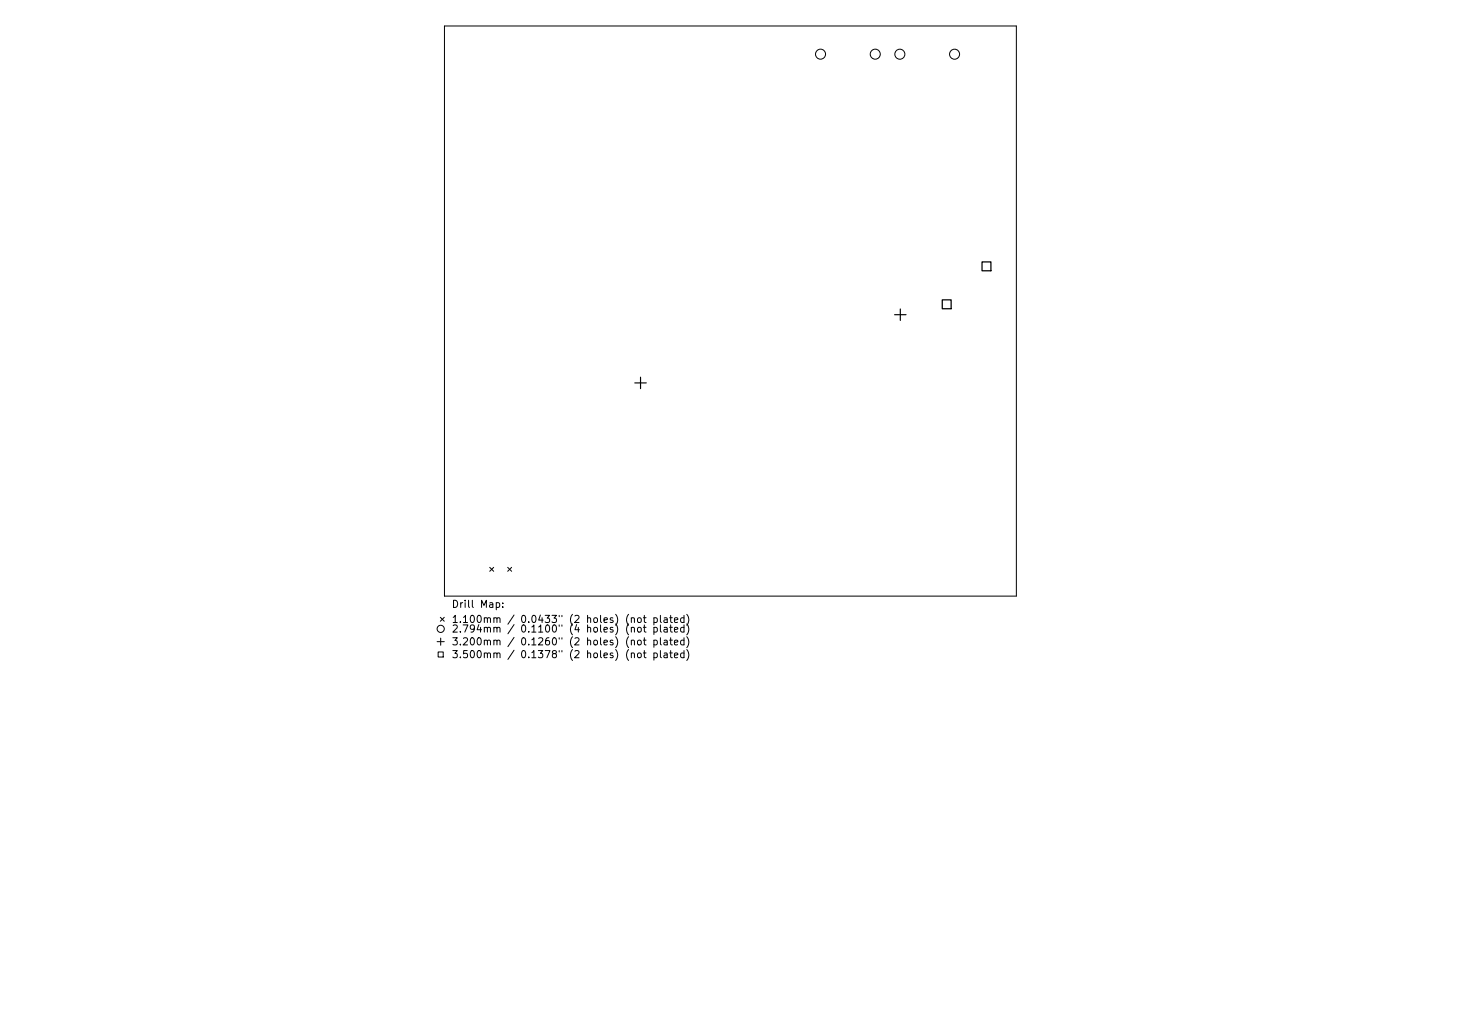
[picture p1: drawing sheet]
<svg xmlns="http://www.w3.org/2000/svg" width="297mm" height="210mm" viewBox="0 0 297 210" stroke-linecap="round" stroke-linejoin="round" font-family="sans-serif">
<defs><g id="words">
<g font-size="2">
<text x="91.8" y="123.6">Drill Map:</text>
<text x="91.8" y="126.7">1.100mm / 0.0433&quot; (2 holes) (not plated)</text>
<text x="91.8" y="128.6">2.794mm / 0.1100&quot; (4 holes) (not plated)</text>
<text x="91.8" y="131.2">3.200mm / 0.1260&quot; (2 holes) (not plated)</text>
<text x="91.8" y="133.8">3.500mm / 0.1378&quot; (2 holes) (not plated)</text>
</g>
</g></defs>
<g fill="none" stroke="#000" stroke-width=".2">
<path d="M90.4 5.3h116.2v115.9h-116.2zM99.6 115.4l.8 .8M100.4 115.4l-.8 .8M103.2 115.4l.8 .8M104 115.4l-.8 .8M88.9 130.5h1.4M89.1 132.6h1v1h-1zM89.5 125.5l.8 .8M89.6 129.7v1.5M90.3 125.5l-.8 .8M100.9 122.6l.4-.1 .3 .3-.1 .6h-.6M102.2 123.4v.1"/>
<path d="M102.2 122.6v.2M128.4 125.8l.2-.2 .3 .1 .1 .9M128.4 127.7l.2-.1h.3l.1 .9M128.4 130.3l.2-.1h.3l.1 .9M128.4 132.9l.2-.1h.3l.1 .9M129.7 125.8l.2-.2 .4 .2 .1 .5-.2 .2-.3 .1-.2-.2zM129.7 130.3l.2-.1 .4 .1 .1 .6-.2 .2h-.3l-.2-.1zM129.7 132.9l.2-.1 .4 .1 .1 .6-.2 .2h-.3l-.2-.1zM129.8 127.6h.3l.3 .2v.5l-.3 .2h-.3l-.2-.2zM130.8 125.6h.6M130.8 127.6h.6M130.8 130.2h.6"/>
<path d="M130.8 132.8h.6M131 125.1v1.3l.4 .2M131 127.1v1.2l.4 .2M131 129.7v1.2l.4 .2M131 132.3v1.2l.4 .2M132.9 125.7l.5-.1 .2 .3-.1 .6h-.6M132.9 127.6h.5l.2 .2-.1 .7h-.6M132.9 130.2h.5l.2 .2-.1 .7h-.6M132.9 132.8h.5l.2 .3-.1 .6h-.6M132.9 125.6v1.5M132.9 127.6v1.4M132.9 130.2v1.4"/>
<path d="M132.9 132.8v1.4M134.3 125.1v1.3l.2 .2M134.3 127.1v1.2l.2 .2M134.3 129.7v1.2l.2 .2M134.3 132.3v1.2l.2 .2M135 125.7h.6l.1 .9M135 127.6h.6l.1 .9M135 130.2h.6l.1 .9M135 132.8h.6l.1 .9M135.7 126h-.5l-.2 .2 .2 .4 .5-.1M135.7 127.9l-.5 .1-.2 .2 .2 .3h.5M135.7 130.5l-.5 .1-.2 .2 .2 .3h.5"/>
<path d="M135.7 133.1l-.5 .1-.2 .2 .2 .3h.5M136.1 125.6h.6M136.1 127.6h.6M136.1 130.2h.6M136.1 132.8h.6M136.4 125.1v1.3l.3 .2M136.4 127.1v1.2l.3 .2M136.4 129.7v1.2l.3 .2M136.4 132.3v1.2l.3 .2M137.1 126.1l.7-.1-.1-.3-.4-.1-.2 .2 .1 .7h.5M137.1 128l.7-.1-.1-.3h-.4l-.2 .2 .1 .7h.5M137.1 130.7l.7-.2-.1-.3h-.4l-.2 .2 .1 .7h.5"/>
<path d="M137.1 133.3l.7-.2-.1-.3h-.4l-.2 .2 .1 .7h.5M139.1 125.7l-.5-.1-.2 .3 .1 .6h.6M139.1 127.6h-.5l-.2 .2 .1 .7h.6M139.1 130.2h-.5l-.2 .2 .1 .7h.6M139.1 132.8h-.5l-.2 .3 .1 .6h.6M139.1 125.1v1.5M139.1 127.1v1.4M139.1 129.7v1.4M139.1 132.3v1.4M139.6 124.9a1.67 1.67 0 0 1 0 2.2M139.6 126.9a1.67 1.67 0 0 1 0 2.2M139.6 129.5a1.67 1.67 0 0 1 0 2.2"/>
<path d="M139.6 132.1a1.67 1.67 0 0 1 0 2.2"/>
<circle cx="166.8" cy="11" r="1.02"/>
<circle cx="177.9" cy="11" r="1.02"/>
<circle cx="182.9" cy="11" r="1.02"/>
<circle cx="194.1" cy="11" r="1.02"/>
<circle cx="89.6" cy="127.9" r=".73"/>
</g>
<path d="M129.1 77.9h2.3M130.2 76.7v2.3M181.9 64h2.3M183 62.8v2.4" fill="none" stroke="#000" stroke-width=".23"/>
<path d="M199.7 53.3h1.8v1.8h-1.8zM191.6 61h1.8v1.8h-1.8z" fill="none" stroke="#000" stroke-width=".26"/>
<use href="#words"/>
</svg>
